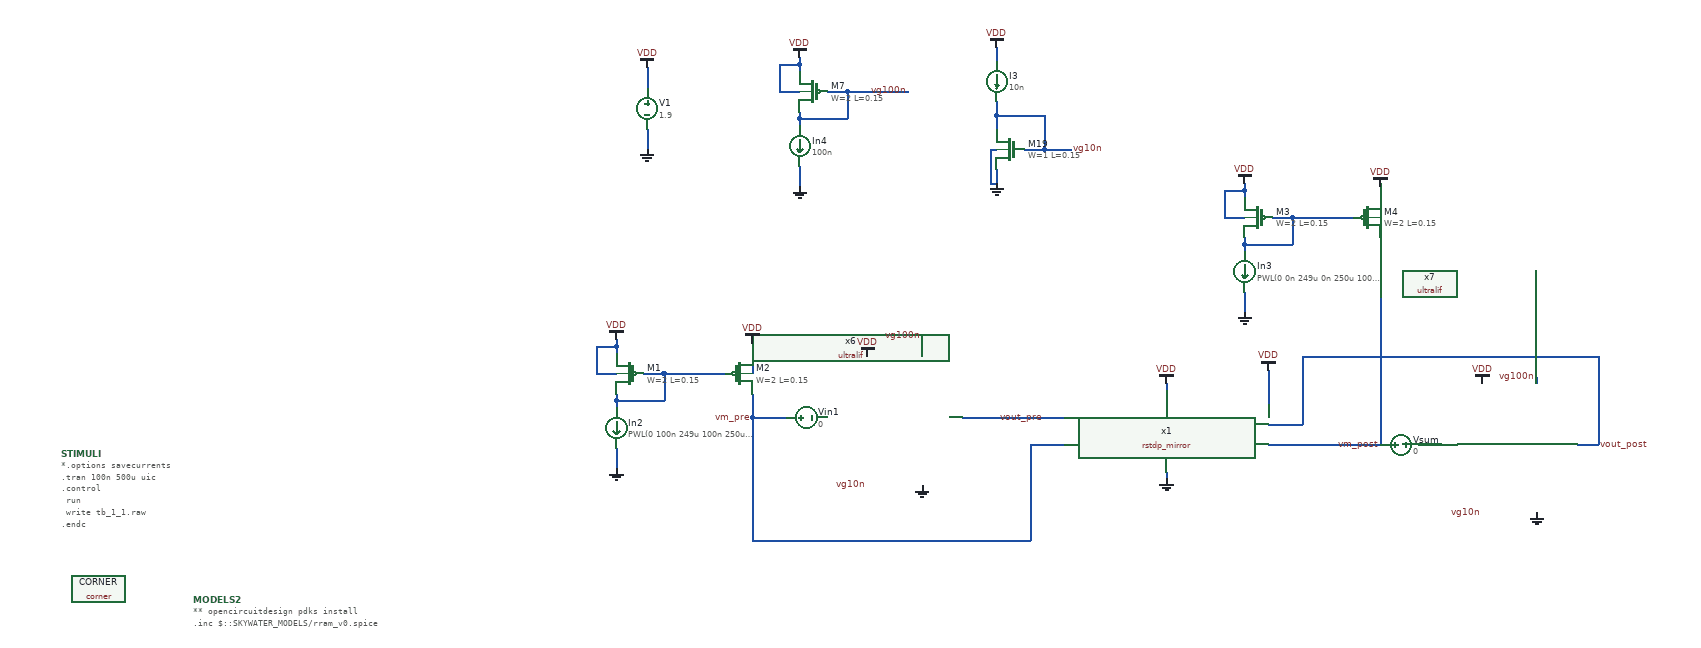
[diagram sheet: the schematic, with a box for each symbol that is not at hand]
v {xschem version=3.4.5 file_version=1.2
}
G {}
K {}
V {}
S {}
E {}
B 2 690 -800 1780 -400 {flags=graph
y1=2.7524304
y2=5.6524304
ypos1=0
ypos2=2
divy=5
subdivy=1
unity=1
x1=1.5625e-11
x2=0.0005
divx=5
subdivx=1
xlabmag=1.0
ylabmag=1.0
node="\\"Fil1; 5 n.x1.x1.xr2.n1#ngap -\\"

\\"Fil2; 5 n.x3.x1.xr2.n1#ngap - \\""
color="6 8"
dataset=-1
unitx=1
logx=0
logy=0
}
B 2 1120 445 2400 815 {flags=graph
y1=-1.2739732
y2=1.3271506
ypos1=0
ypos2=2
divy=5
subdivy=1
unity=1
x1=1.5625e-11
x2=0.0005
divx=5
subdivx=1
xlabmag=1.0
ylabmag=1.0


dataset=-1
unitx=1
logx=0
logy=0
color=4
node="\\"Vmem1; x1.x1.BE x1.x1.TE - \\""}
B 2 1580 -60 2380 340 {flags=graph
y1=-0.0023
y2=1.9
ypos1=0
ypos2=2
divy=5
subdivy=1
unity=1
x1=1.5625e-11
x2=0.0005
divx=5
subdivx=1
xlabmag=1.0
ylabmag=1.0


dataset=-1
unitx=1
logx=0
logy=0
color=8
node=vout_post}
B 2 -1137.5 -425 -337.5 -25 {flags=graph
y1=-0.00026
y2=2.5
ypos1=0
ypos2=2
divy=5
subdivy=1
unity=1
x1=1.5625e-11
x2=0.0005
divx=5
subdivx=1
xlabmag=1.0
ylabmag=1.0


dataset=-1
unitx=1
logx=0
logy=0
color=6
node=vout_pre}
B 2 -190 -890 610 -490 {flags=graph
y1=-7.8149354e-07
y2=8.7499777e-07
ypos1=0
ypos2=2
divy=5
subdivy=1
unity=1
x1=1.5625e-11
x2=0.0005
divx=5
subdivx=1
xlabmag=1.0
ylabmag=1.0


dataset=-1
unitx=1
logx=0
logy=0
color=6
node=i(Vsum)}
B 2 1562.5 -485 2362.5 -85 {flags=graph
y1=0.126
y2=1.71
ypos1=0
ypos2=2
divy=5
subdivy=1
unity=1
x1=1.5625e-11
x2=0.0005
divx=5
subdivx=1
xlabmag=1.0
ylabmag=1.0


dataset=-1
unitx=1
logx=0
logy=0




color="4 7"
node="x7.vm
\\"Vth; 1.5\\""}
B 2 -217.5 420 582.5 820 {flags=graph
y1=-5.4508987e-07
y2=7.5470672e-07
ypos1=0
ypos2=2
divy=5
subdivy=1
unity=1
x1=1.5625e-11
x2=0.0005
divx=5
subdivx=1
xlabmag=1.0
ylabmag=1.0


dataset=-1
unitx=1
logx=0
logy=0




color=6
node=i(vin1)}
B 2 -1125 492.5 -325 892.5 {flags=graph
y1=0.3185
y2=1.9025
ypos1=0
ypos2=2
divy=5
subdivy=1
unity=1
x1=1.5625e-11
x2=0.0005
divx=5
subdivx=1
xlabmag=1.0
ylabmag=1.0


dataset=-1
unitx=1
logx=0
logy=0

color=6
node=x6.vm}
N -215 -325 -215 -295 {
lab=GND}
N -215 -415 -215 -385 {
lab=VDD}
N 300 -345 300 -325 {
lab=vg10n}
N 300 -445 300 -425 {
lab=VDD}
N 300 -265 300 -245 {
lab=GND}
N 290 -295 300 -295 {
lab=GND}
N 290 -295 290 -245 {
lab=GND}
N 290 -245 300 -245 {
lab=GND}
N 370 -295 410 -295 {
lab=vg10n}
N 300 -345 370 -345 {
lab=vg10n}
N 370 -345 370 -295 {
lab=vg10n}
N 550 50 550 60 {
lab=VDD}
N 550 180 550 190 {
lab=GND}
N 1155 140 1185 140 {
lab=vout_post}
N 1185 10 1185 140 {
lab=vout_post}
N 10 -420 10 -410 {
lab=VDD}
N -20 -380 10 -380 {
lab=VDD}
N -20 -420 -20 -380 {
lab=VDD}
N -20 -420 10 -420 {
lab=VDD}
N 50 -380 80 -380 {
lab=vg100n}
N 10 -340 10 -330 {
lab=vg100n}
N 10 -340 80 -340 {
lab=vg100n}
N 80 -380 80 -340 {
lab=vg100n}
N 80 -380 170 -380 {
lab=vg100n}
N 190 -20 190 10 {
lab=vg100n}
N 1095 40 1095 50 {
lab=vg100n}
N 250 100 400 100 {
lab=vout_pre}
N 10 -270 10 -240 {
lab=GND}
N -60 100 -10 100 {
lab=vm_pre}
N -60 280 350 280 {
lab=vm_pre}
N -60 100 -60 280 {
lab=vm_pre}
N 700 140 865 140 {
lab=vm_post}
N 750 10 750 110 {
lab=vout_post}
N 700 110 750 110 {
lab=vout_post}
N 920 140 955 140 {
lab=#net1}
N 750 10 1185 10 {
lab=vout_post}
N 350 140 350 280 {
lab=vm_pre}
N -60 -15 -60 35 {
lab=VDD}
N -260 -5 -260 5 {
lab=VDD}
N -290 35 -260 35 {
lab=VDD}
N -290 -5 -290 35 {
lab=VDD}
N -290 -5 -260 -5 {
lab=VDD}
N -220 35 -190 35 {
lab=#net2}
N -260 75 -260 85 {
lab=#net2}
N -260 75 -190 75 {
lab=#net2}
N -190 35 -190 75 {
lab=#net2}
N -190 35 -100 35 {
lab=#net2}
N -260 145 -260 175 {
lab=GND}
N -60 65 -60 100 {
lab=vm_pre}
N 865 -245 865 -195 {
lab=VDD}
N 665 -235 665 -225 {
lab=VDD}
N 635 -195 665 -195 {
lab=VDD}
N 635 -235 635 -195 {
lab=VDD}
N 635 -235 665 -235 {
lab=VDD}
N 705 -195 735 -195 {
lab=#net3}
N 665 -155 665 -145 {
lab=#net3}
N 665 -155 735 -155 {
lab=#net3}
N 735 -195 735 -155 {
lab=#net3}
N 735 -195 825 -195 {
lab=#net3}
N 665 -85 665 -55 {
lab=GND}
N 865 -165 865 140 {
lab=vm_post}
N 700 30 700 80 {
lab=VDD}
N 300 -365 300 -345 {
lab=vg10n}
N 340 -295 370 -295 {
lab=vg10n}
N 10 -430 10 -420 {
lab=VDD}
N 10 -350 10 -340 {
lab=vg100n}
N 350 140 400 140 {
lab=vm_pre}
N -260 -15 -260 -5 {
lab=VDD}
N -260 65 -260 75 {
lab=#net2}
N 665 -245 665 -235 {
lab=VDD}
N 665 -165 665 -155 {
lab=#net3}
C {devices/vsource.sym} -215 -355 0 0 {name=V1 value=1.9 savecurrent=false}
C {devices/vdd.sym} -215 -415 0 0 {name=l1 lab=VDD}
C {devices/gnd.sym} -215 -295 0 0 {name=l2 lab=GND}
C {sky130_fd_pr/corner.sym} -1022.5 352.5 0 0 {name=CORNER only_toplevel=true corner=tt}
C {devices/code_shown.sym} -1077.5 152.5 0 0 {name=STIMULI 
only_toplevel=true
place=end
value="
*.options savecurrents
.tran 100n 500u uic
.control
	run
	write tb_1_1.raw
.endc
"}
C {devices/code.sym} -882.5 367.5 0 0 {name=MODELS2
only_toplevel=true
format="tcleval( @value )"
value="
** opencircuitdesign pdks install
.inc $::SKYWATER_MODELS/rram_v0.spice
"
spice_ignore=false}
C {/home/alex/Desktop/EDA/SNN_IPN/Neuron/ultralif/ultralif.sym} 150 100 0 0 {name=x6}
C {/home/alex/Desktop/EDA/SNN_IPN/Neuron/ultralif/ultralif.sym} 1055 140 0 0 {name=x7}
C {sky130_fd_pr/nfet_01v8.sym} 320 -295 0 1 {name=M19
L=0.15
W=1
nf=1 
mult=1
ad="'int((nf+1)/2) * W/nf * 0.29'" 
pd="'2*int((nf+1)/2) * (W/nf + 0.29)'"
as="'int((nf+2)/2) * W/nf * 0.29'" 
ps="'2*int((nf+2)/2) * (W/nf + 0.29)'"
nrd="'0.29 / W'" nrs="'0.29 / W'"
sa=0 sb=0 sd=0
model=nfet_01v8
spiceprefix=X
}
C {devices/isource.sym} 300 -395 0 0 {name=I3 value=10n}
C {devices/vdd.sym} 300 -445 0 0 {name=l30 lab=VDD}
C {devices/gnd.sym} 300 -245 0 0 {name=l31 lab=GND}
C {devices/vdd.sym} 110 10 0 0 {name=l3 lab=VDD}
C {devices/gnd.sym} 190 200 0 0 {name=l4 lab=GND}
C {devices/gnd.sym} 1095 240 0 0 {name=l5 lab=GND}
C {devices/vdd.sym} 1015 50 0 0 {name=l6 lab=VDD}
C {devices/vdd.sym} 550 50 0 0 {name=l10 lab=VDD}
C {devices/gnd.sym} 550 190 0 0 {name=l11 lab=GND}
C {devices/lab_pin.sym} 370 100 1 0 {name=p1 sig_type=std_logic lab=vout_pre}
C {devices/lab_pin.sym} 1185 140 0 1 {name=p3 sig_type=std_logic lab=vout_post}
C {devices/launcher.sym} -577.5 242.5 0 0 {name=h5
descr="load waves" 
tclcommand="xschem raw_read $netlist_dir/tb_1_1.raw tran"
}
C {sky130_fd_pr/pfet_01v8.sym} 30 -380 0 1 {name=M7
L=0.15
W=2
nf=1
mult=1
ad="'int((nf+1)/2) * W/nf * 0.29'" 
pd="'2*int((nf+1)/2) * (W/nf + 0.29)'"
as="'int((nf+2)/2) * W/nf * 0.29'" 
ps="'2*int((nf+2)/2) * (W/nf + 0.29)'"
nrd="'0.29 / W'" nrs="'0.29 / W'"
sa=0 sb=0 sd=0
model=pfet_01v8
spiceprefix=X
}
C {devices/vdd.sym} 10 -430 0 0 {name=l8 lab=VDD}
C {devices/isource.sym} 10 -300 0 1 {name=In4 value=100n }
C {devices/lab_pin.sym} 170 -380 3 0 {name=p7 sig_type=std_logic lab=vg100n}
C {devices/lab_pin.sym} 190 -20 1 0 {name=p8 sig_type=std_logic lab=vg100n}
C {devices/lab_pin.sym} 1095 40 1 0 {name=p11 sig_type=std_logic lab=vg100n}
C {/home/alex/Desktop/EDA/SNN_IPN/Synapse/rstdp_mirror.sym} 550 100 0 0 {name=x1}
C {devices/isource.sym} -260 115 0 1 {name=In2 value="PWL(0 100n 249u 100n 250u 0n)"
spice_ignore=false}
C {devices/vsource.sym} 895 140 3 0 {name=Vsum value=0 }
C {devices/isource.sym} 665 -115 0 1 {name=In3 value="PWL(0 0n 249u 0n 250u 100n)"
spice_ignore=false}
C {devices/lab_pin.sym} 410 -295 2 0 {name=p6 sig_type=std_logic lab=vg10n}
C {devices/lab_pin.sym} 110 200 3 0 {name=p12 sig_type=std_logic lab=vg10n}
C {devices/lab_pin.sym} 1015 240 3 0 {name=p13 sig_type=std_logic lab=vg10n}
C {devices/gnd.sym} 10 -240 0 0 {name=l17 lab=GND}
C {devices/vsource.sym} 20 100 3 0 {name=Vin1 value=0 }
C {devices/vdd.sym} -60 -10 0 0 {name=l18 lab=VDD}
C {devices/lab_pin.sym} -60 100 0 0 {name=p2 sig_type=std_logic lab=vm_pre}
C {devices/lab_pin.sym} 865 140 3 0 {name=p4 sig_type=std_logic lab=vm_post}
C {sky130_fd_pr/pfet_01v8.sym} -240 35 0 1 {name=M1
L=0.15
W=2
nf=1
mult=1
ad="'int((nf+1)/2) * W/nf * 0.29'" 
pd="'2*int((nf+1)/2) * (W/nf + 0.29)'"
as="'int((nf+2)/2) * W/nf * 0.29'" 
ps="'2*int((nf+2)/2) * (W/nf + 0.29)'"
nrd="'0.29 / W'" nrs="'0.29 / W'"
sa=0 sb=0 sd=0
model=pfet_01v8
spiceprefix=X
}
C {devices/vdd.sym} -260 -15 0 0 {name=l7 lab=VDD}
C {devices/gnd.sym} -260 175 0 0 {name=l12 lab=GND}
C {sky130_fd_pr/pfet_01v8.sym} -80 35 0 0 {name=M2
L=0.15
W=2
nf=1
mult=1
ad="'int((nf+1)/2) * W/nf * 0.29'" 
pd="'2*int((nf+1)/2) * (W/nf + 0.29)'"
as="'int((nf+2)/2) * W/nf * 0.29'" 
ps="'2*int((nf+2)/2) * (W/nf + 0.29)'"
nrd="'0.29 / W'" nrs="'0.29 / W'"
sa=0 sb=0 sd=0
model=pfet_01v8
spiceprefix=X
}
C {devices/vdd.sym} 865 -240 0 0 {name=l13 lab=VDD}
C {sky130_fd_pr/pfet_01v8.sym} 685 -195 0 1 {name=M3
L=0.15
W=2
nf=1
mult=1
ad="'int((nf+1)/2) * W/nf * 0.29'" 
pd="'2*int((nf+1)/2) * (W/nf + 0.29)'"
as="'int((nf+2)/2) * W/nf * 0.29'" 
ps="'2*int((nf+2)/2) * (W/nf + 0.29)'"
nrd="'0.29 / W'" nrs="'0.29 / W'"
sa=0 sb=0 sd=0
model=pfet_01v8
spiceprefix=X
}
C {devices/vdd.sym} 665 -245 0 0 {name=l14 lab=VDD}
C {devices/gnd.sym} 665 -55 0 0 {name=l15 lab=GND}
C {sky130_fd_pr/pfet_01v8.sym} 845 -195 0 0 {name=M4
L=0.15
W=2
nf=1
mult=1
ad="'int((nf+1)/2) * W/nf * 0.29'" 
pd="'2*int((nf+1)/2) * (W/nf + 0.29)'"
as="'int((nf+2)/2) * W/nf * 0.29'" 
ps="'2*int((nf+2)/2) * (W/nf + 0.29)'"
nrd="'0.29 / W'" nrs="'0.29 / W'"
sa=0 sb=0 sd=0
model=pfet_01v8
spiceprefix=X
}
C {devices/vdd.sym} 700 30 0 0 {name=l9 lab=VDD}
